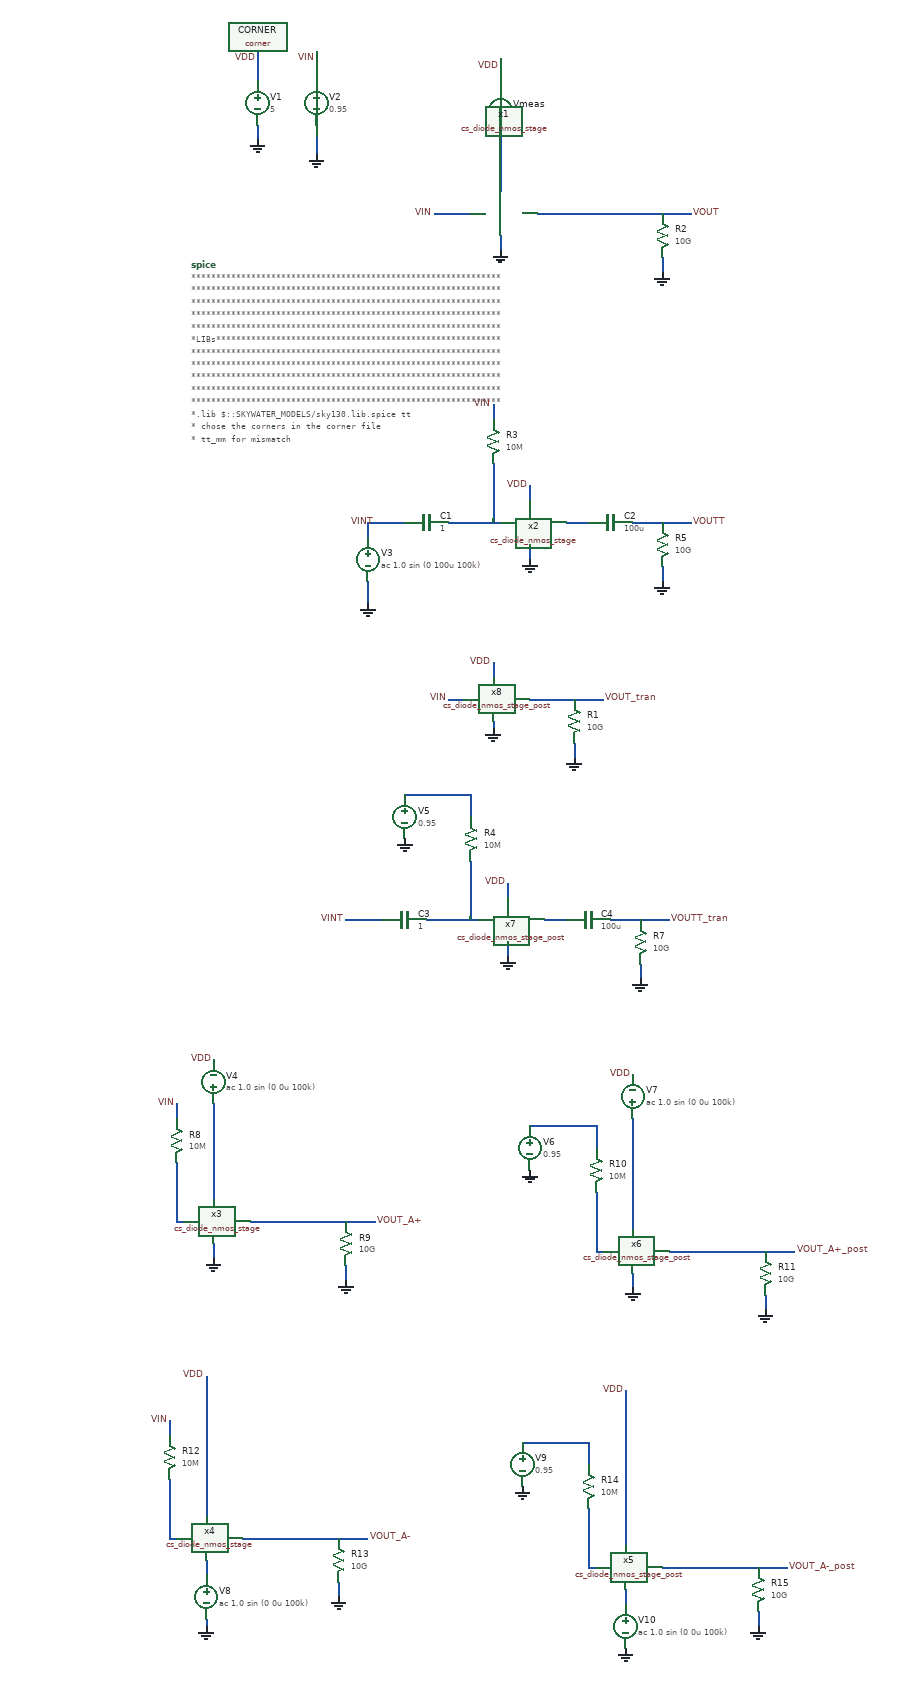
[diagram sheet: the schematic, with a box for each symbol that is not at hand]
v {xschem version=3.4.2 file_version=1.2
}
G {}
K {}
V {}
S {}
E {}
N 100 -350 100 -330 {
lab=GND}
N 100 -450 100 -410 {
lab=VDD}
N 430 -440 430 -400 {
lab=VDD}
N 180 -350 180 -330 {
lab=GND}
N 180 -450 180 -410 {
lab=VIN}
N 340 -230 390 -230 {
lab=VIN}
N 180 -330 180 -310 {
lab=GND}
N 250 270 250 300 {
lab=GND}
N 650 -230 690 -230 {
lab=VOUT}
N 480 -230 650 -230 {
lab=VOUT}
N 650 -170 650 -150 {
lab=GND}
N 250 190 300 190 {
lab=VINT}
N 250 190 250 210 {
lab=VINT}
N 360 190 430 190 {
lab=#net1}
N 650 190 690 190 {
lab=VOUTT}
N 650 250 650 270 {
lab=GND}
N 610 190 650 190 {
lab=VOUTT}
N 520 190 550 190 {
lab=#net2}
N 420 110 420 190 {
lab=#net1}
N 420 30 420 50 {
lab=VIN}
N 470 140 470 160 {
lab=VDD}
N 470 220 470 240 {
lab=GND}
N 360 430 380 430 {
lab=VIN}
N 420 380 420 400 {
lab=VDD}
N 420 460 420 470 {
lab=GND}
N 530 430 570 430 {
lab=VOUT_tran}
N 530 490 530 510 {
lab=GND}
N 470 430 530 430 {
lab=VOUT_tran}
N 220 730 270 730 {
lab=VINT}
N 330 730 400 730 {
lab=#net3}
N 620 730 660 730 {
lab=VOUTT_tran}
N 620 790 620 810 {
lab=GND}
N 580 730 620 730 {
lab=VOUTT_tran}
N 490 730 520 730 {
lab=#net4}
N 390 650 390 730 {
lab=#net3}
N 390 570 390 590 {
lab=#net5}
N 440 680 440 700 {
lab=VDD}
N 440 760 440 780 {
lab=GND}
N 300 560 380 560 {
lab=#net5}
N 380 560 390 560 {
lab=#net5}
N 390 560 390 570 {
lab=#net5}
N 220 1140 260 1140 {
lab=VOUT_A+}
N 220 1200 220 1220 {
lab=GND}
N 180 1140 220 1140 {
lab=VOUT_A+}
N 90 1140 120 1140 {
lab=VOUT_A+}
N -10 1060 -10 1140 {
lab=#net6}
N -10 980 -10 1000 {
lab=VIN}
N 40 1090 40 1110 {
lab=#net7}
N 40 1170 40 1190 {
lab=GND}
N 40 980 40 1090 {
lab=#net7}
N 790 1180 830 1180 {
lab=VOUT_A+_post}
N 790 1240 790 1260 {
lab=GND}
N 750 1180 790 1180 {
lab=VOUT_A+_post}
N 660 1180 690 1180 {
lab=VOUT_A+_post}
N 560 1100 560 1180 {
lab=#net8}
N 560 1020 560 1040 {
lab=#net9}
N 610 1130 610 1150 {
lab=#net10}
N 610 1210 610 1230 {
lab=GND}
N 470 1010 550 1010 {
lab=#net9}
N 550 1010 560 1010 {
lab=#net9}
N 560 1010 560 1020 {
lab=#net9}
N 610 1110 610 1130 {
lab=#net10}
N 610 1000 610 1110 {
lab=#net10}
N 690 1180 750 1180 {
lab=VOUT_A+_post}
N 120 1140 180 1140 {
lab=VOUT_A+}
N 210 1570 250 1570 {
lab=VOUT_A-}
N 210 1630 210 1650 {
lab=GND}
N 170 1570 210 1570 {
lab=VOUT_A-}
N 80 1570 110 1570 {
lab=VOUT_A-}
N -20 1490 -20 1570 {
lab=#net11}
N -20 1410 -20 1430 {
lab=VIN}
N 30 1520 30 1540 {
lab=VDD}
N 30 1600 30 1620 {
lab=#net12}
N 30 1410 30 1520 {
lab=VDD}
N 780 1610 820 1610 {
lab=VOUT_A-_post}
N 780 1670 780 1690 {
lab=GND}
N 740 1610 780 1610 {
lab=VOUT_A-_post}
N 650 1610 680 1610 {
lab=VOUT_A-_post}
N 550 1530 550 1610 {
lab=#net13}
N 550 1450 550 1470 {
lab=#net14}
N 600 1560 600 1580 {
lab=VDD}
N 600 1640 600 1660 {
lab=#net15}
N 460 1440 540 1440 {
lab=#net14}
N 540 1440 550 1440 {
lab=#net14}
N 550 1440 550 1450 {
lab=#net14}
N 600 1540 600 1560 {
lab=VDD}
N 600 1430 600 1540 {
lab=VDD}
N 680 1610 740 1610 {
lab=VOUT_A-_post}
N 110 1570 170 1570 {
lab=VOUT_A-}
N 30 1350 30 1410 {
lab=VDD}
N 30 1680 30 1690 {
lab=GND}
N 600 1370 600 1430 {
lab=VDD}
N 560 1180 570 1180 {
lab=#net8}
N -10 1140 0 1140 {
lab=#net6}
N -20 1570 -10 1570 {
lab=#net11}
N 550 1610 560 1610 {
lab=#net13}
N 430 -340 430 -260 {
lab=#net16}
N 430 -200 430 -180 {
lab=GND}
C {devices/code.sym} 10 -160 0 0 {name=spice only_toplevel=false
format="tcleval( @value )"
value="	
**************************************************************
**************************************************************
**************************************************************
**************************************************************
**************************************************************
*LIBs*********************************************************
**************************************************************
**************************************************************
**************************************************************
**************************************************************
**************************************************************
*.lib $::SKYWATER_MODELS/sky130.lib.spice tt
* chose the corners in the corner file
* tt_mm for mismatch
* ss ff sf fs standart corners
* ll hh lh hl capacitor and resistors corners
* mc for total process variation including corners
**************************************************************
**************************************************************
**************************************************************
**************************************************************
**************************************************************
*Corners/montecarlo options***********************************
**************************************************************
**************************************************************
**************************************************************
**************************************************************
**************************************************************
.TEMP 27
.include ~/Documents/cs_diode_nmos_stage_post.spice
**************************************************************
**************************************************************
**************************************************************
**************************************************************  
*SIMULATION and Plots*****************************************
**************************************************************
**************************************************************
**************************************************************
**************************************************************
.control
save all
dc V2 0 5 0.01 
*dc simulation
plot v(VOUT) v(VIN) deriv(v(VOUT)) v(VOUt_tran) deriv(v(VOUT_tran))
*ploting VIN VOUT and the voltage gain
plot i(Vmeas) 
*ploting the current for curiosity
tran 1ns 20u 
*transient simulation
plot (v(VINT)) (v(VOUTT)) v(VOUTT_tran)
*simple plot to exemplify the gain
fft v(VOUTT) v(VINT) v(VOUTT_tran)
*fast fourier transfor
plot mag(v(VOUTT)) mag(v(VINT)) mag(v(VOUTT_tran))
* analyse the frequency spectrum of the transient waves, to detect distortion
ac dec 20 1 50G 
*simple ac simulation
plot db(v(VOUTT)) db(v(VOUTT_tran))
plot db(v(VOUT_A+)) db(v(VOUT_A+_post))
plot db(v(VOUT_A-)) db(v(VOUT_A-_post))
*gain in function of the input frequency
.endc
"}
C {devices/ammeter.sym} 430 -370 0 0 {name=Vmeas}
C {devices/lab_pin.sym} 100 -440 0 0 {name=p1 sig_type=std_logic lab=VDD}
C {devices/vsource.sym} 100 -380 0 0 {name=V1 value=5
}
C {devices/vsource.sym} 180 -380 0 0 {name=V2 value=0.95}
C {devices/gnd.sym} 100 -330 0 0 {name=l3 lab=GND}
C {devices/lab_pin.sym} 430 -430 0 0 {name=p2 sig_type=std_logic lab=VDD}
C {devices/gnd.sym} 250 300 0 0 {name=l4 lab=GND}
C {devices/lab_pin.sym} 180 -440 0 0 {name=p3 sig_type=std_logic lab=VIN
}
C {devices/lab_pin.sym} 690 -230 2 0 {name=p5 sig_type=std_logic lab=VOUT}
C {devices/vsource.sym} 250 240 0 0 {name=V3 value="ac 1.0 sin (0 100u 100k)"}
C {devices/lab_pin.sym} 340 -230 0 0 {name=p4 sig_type=std_logic lab=VIN
}
C {devices/gnd.sym} 180 -310 0 0 {name=l5 lab=GND}
C {devices/res.sym} 650 -200 0 0 {name=R2
value=10G
footprint=1206
device=resistor
m=1}
C {devices/gnd.sym} 650 -150 0 0 {name=l6 lab=GND}
C {devices/capa.sym} 330 190 3 0 {name=C1
m=1
value=1
footprint=1206
device="ceramic capacitor"}
C {devices/lab_pin.sym} 420 30 0 0 {name=p6 sig_type=std_logic lab=VIN
}
C {devices/res.sym} 420 80 0 0 {name=R3
value=10M
footprint=1206
device=resistor
m=1}
C {devices/res.sym} 650 220 0 0 {name=R5
value=10G
footprint=1206
device=resistor
m=1}
C {devices/gnd.sym} 650 270 0 0 {name=l9 lab=GND}
C {devices/lab_pin.sym} 690 190 2 0 {name=p8 sig_type=std_logic lab=VOUTT}
C {devices/lab_pin.sym} 260 190 1 0 {name=p9 sig_type=std_logic lab=VINT
}
C {sky130_fd_pr/corner.sym} -160 -160 0 0 {name=CORNER only_toplevel=true corner=tt}
C {devices/capa.sym} 580 190 3 0 {name=C2
m=1
value=100u
footprint=1206
device="ceramic capacitor"}
C {devices/lab_pin.sym} 470 140 1 0 {name=p7 sig_type=std_logic lab=VDD}
C {devices/gnd.sym} 470 240 0 0 {name=l7 lab=GND}
C {devices/lab_pin.sym} 360 430 0 0 {name=p11 sig_type=std_logic lab=VIN
}
C {devices/lab_pin.sym} 420 380 1 0 {name=p12 sig_type=std_logic lab=VDD}
C {devices/gnd.sym} 420 470 0 0 {name=l8 lab=GND}
C {devices/lab_pin.sym} 570 430 2 0 {name=p13 sig_type=std_logic lab=VOUT_tran}
C {devices/res.sym} 530 460 0 0 {name=R1
value=10G
footprint=1206
device=resistor
m=1}
C {devices/gnd.sym} 530 510 0 0 {name=l10 lab=GND}
C {devices/capa.sym} 300 730 3 0 {name=C3
m=1
value=1
footprint=1206
device="ceramic capacitor"}
C {devices/res.sym} 390 620 0 0 {name=R4
value=10M
footprint=1206
device=resistor
m=1}
C {devices/res.sym} 620 760 0 0 {name=R7
value=10G
footprint=1206
device=resistor
m=1}
C {devices/gnd.sym} 620 810 0 0 {name=l12 lab=GND}
C {devices/lab_pin.sym} 660 730 2 0 {name=p15 sig_type=std_logic lab=VOUTT_tran}
C {devices/capa.sym} 550 730 3 0 {name=C4
m=1
value=100u
footprint=1206
device="ceramic capacitor"}
C {devices/lab_pin.sym} 440 680 1 0 {name=p17 sig_type=std_logic lab=VDD}
C {devices/gnd.sym} 440 780 0 0 {name=l13 lab=GND}
C {devices/vsource.sym} 300 590 0 0 {name=V5 value=0.95}
C {devices/lab_pin.sym} 220 730 1 0 {name=p14 sig_type=std_logic lab=VINT
}
C {devices/gnd.sym} 300 620 0 0 {name=l11 lab=GND}
C {devices/vsource.sym} 40 950 2 0 {name=V4 value="ac 1.0 sin (0 0u 100k)"}
C {devices/lab_pin.sym} -10 980 0 0 {name=p16 sig_type=std_logic lab=VIN
}
C {devices/res.sym} -10 1030 0 0 {name=R8
value=10M
footprint=1206
device=resistor
m=1}
C {devices/res.sym} 220 1170 0 0 {name=R9
value=10G
footprint=1206
device=resistor
m=1}
C {devices/gnd.sym} 220 1220 0 0 {name=l15 lab=GND}
C {devices/lab_pin.sym} 260 1140 2 0 {name=p18 sig_type=std_logic lab=VOUT_A+}
C {devices/lab_pin.sym} 40 920 1 0 {name=p20 sig_type=std_logic lab=VDD}
C {devices/gnd.sym} 40 1190 0 0 {name=l16 lab=GND}
C {devices/res.sym} 560 1070 0 0 {name=R10
value=10M
footprint=1206
device=resistor
m=1}
C {devices/res.sym} 790 1210 0 0 {name=R11
value=10G
footprint=1206
device=resistor
m=1}
C {devices/gnd.sym} 790 1260 0 0 {name=l14 lab=GND}
C {devices/lab_pin.sym} 830 1180 2 0 {name=p19 sig_type=std_logic lab=VOUT_A+_post}
C {devices/gnd.sym} 610 1230 0 0 {name=l17 lab=GND}
C {devices/vsource.sym} 470 1040 0 0 {name=V6 value=0.95}
C {devices/gnd.sym} 470 1070 0 0 {name=l18 lab=GND}
C {devices/vsource.sym} 610 970 2 0 {name=V7 value="ac 1.0 sin (0 0u 100k)"}
C {devices/lab_pin.sym} 610 940 1 0 {name=p21 sig_type=std_logic lab=VDD}
C {devices/vsource.sym} 30 1650 0 0 {name=V8 value="ac 1.0 sin (0 0u 100k)"}
C {devices/lab_pin.sym} -20 1410 0 0 {name=p22 sig_type=std_logic lab=VIN
}
C {devices/res.sym} -20 1460 0 0 {name=R12
value=10M
footprint=1206
device=resistor
m=1}
C {devices/res.sym} 210 1600 0 0 {name=R13
value=10G
footprint=1206
device=resistor
m=1}
C {devices/gnd.sym} 210 1650 0 0 {name=l19 lab=GND}
C {devices/lab_pin.sym} 250 1570 2 0 {name=p23 sig_type=std_logic lab=VOUT_A-}
C {devices/lab_pin.sym} 30 1350 1 0 {name=p24 sig_type=std_logic lab=VDD}
C {devices/gnd.sym} 30 1690 0 0 {name=l20 lab=GND}
C {devices/res.sym} 550 1500 0 0 {name=R14
value=10M
footprint=1206
device=resistor
m=1}
C {devices/res.sym} 780 1640 0 0 {name=R15
value=10G
footprint=1206
device=resistor
m=1}
C {devices/gnd.sym} 780 1690 0 0 {name=l21 lab=GND}
C {devices/lab_pin.sym} 820 1610 2 0 {name=p25 sig_type=std_logic lab=VOUT_A-_post}
C {devices/gnd.sym} 600 1720 0 0 {name=l22 lab=GND}
C {devices/vsource.sym} 460 1470 0 0 {name=V9 value=0.95}
C {devices/gnd.sym} 460 1500 0 0 {name=l23 lab=GND}
C {devices/vsource.sym} 600 1690 0 0 {name=V10 value="ac 1.0 sin (0 0u 100k)"}
C {devices/lab_pin.sym} 600 1370 1 0 {name=p26 sig_type=std_logic lab=VDD}
C {/home/vasco/Desktop/sky130A/amp_tests/basic_stages/cs_diode_nmos_stage/cs_diode_nmos_stage.sym} 510 -230 0 0 {name=x1}
C {devices/gnd.sym} 430 -180 0 0 {name=l1 lab=GND}
C {/home/vasco/Desktop/sky130A/amp_tests/basic_stages/cs_diode_nmos_stage/cs_diode_nmos_stage.sym} 550 190 0 0 {name=x2}
C {/home/vasco/Desktop/sky130A/amp_tests/basic_stages/cs_diode_nmos_stage/cs_diode_nmos_stage.sym} 120 1140 0 0 {name=x3}
C {/home/vasco/Desktop/sky130A/amp_tests/basic_stages/cs_diode_nmos_stage/cs_diode_nmos_stage.sym} 110 1570 0 0 {name=x4}
C {/home/vasco/Desktop/sky130A/amp_tests/basic_stages/cs_diode_nmos_stage/cs_diode_nmos_stage_post.sym} 680 1610 0 0 {name=x5}
C {/home/vasco/Desktop/sky130A/amp_tests/basic_stages/cs_diode_nmos_stage/cs_diode_nmos_stage_post.sym} 690 1180 0 0 {name=x6}
C {/home/vasco/Desktop/sky130A/amp_tests/basic_stages/cs_diode_nmos_stage/cs_diode_nmos_stage_post.sym} 520 730 0 0 {name=x7}
C {/home/vasco/Desktop/sky130A/amp_tests/basic_stages/cs_diode_nmos_stage/cs_diode_nmos_stage_post.sym} 500 430 0 0 {name=x8}
